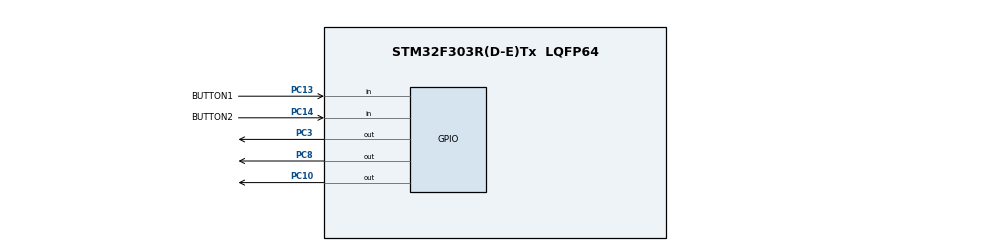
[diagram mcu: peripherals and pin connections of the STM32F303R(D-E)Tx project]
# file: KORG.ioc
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Mcu.Family=STM32F3
Mcu.Name=STM32F303R(D-E)Tx
Mcu.Package=LQFP64
NVIC.PriorityGroup=NVIC_PRIORITYGROUP_4
NVIC.TIM1_UP_TIM16_IRQn=true\:0\:0\:false\:false\:true\:true\:true
PC10.Signal=GPIO_Output
PC13.GPIO_Label=BUTTON1
PC13.Signal=GPIO_Input
PC14-OSC32_IN.GPIO_Label=BUTTON2
PC14-OSC32_IN.Signal=GPIO_Input
PC3.Signal=GPIO_Output
PC8.Signal=GPIO_Output
ProjectManager.HeapSize=0x200
ProjectManager.StackSize=0x400
ProjectManager.TargetToolchain=STM32CubeIDE
RCC.AHBFreq_Value=24000000
RCC.APB1Freq_Value=24000000
RCC.APB1TimFreq_Value=24000000
RCC.APB2CLKDivider=RCC_HCLK_DIV4
RCC.APB2Freq_Value=6000000
RCC.APB2TimFreq_Value=12000000
RCC.CortexFreq_Value=24000000
RCC.HCLKFreq_Value=24000000
RCC.HSE_VALUE=8000000
RCC.HSI_VALUE=8000000
RCC.LSE_VALUE=32768
RCC.PLLMUL=RCC_PLL_MUL3
RCC.SYSCLKFreq_VALUE=24000000
RCC.SYSCLKSourceVirtual=RCC_SYSCLKSOURCE_PLLCLK
RCC.USBFreq_Value=24000000
TIM1.Period=3999
TIM1.TIM_MasterOutputTrigger=TIM_TRGO_UPDATE
VP_TIM1_VS_ClockSourceINT.Mode=Internal
board=custom

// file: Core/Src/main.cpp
/* USER CODE BEGIN Header */
/**
  ******************************************************************************
  * @file           : main.c
  * @brief          : Main program body
  ******************************************************************************
  * @attention
  *
  * <h2><center>&copy; Copyright (c) 2022 STMicroelectronics.
  * All rights reserved.</center></h2>
  *
  * This software component is licensed by ST under BSD 3-Clause license,
  * the "License"; You may not use this file except in compliance with the
  * License. You may obtain a copy of the License at:
  *                        opensource.org/licenses/BSD-3-Clause
  *
  ******************************************************************************
  */
/* USER CODE END Header */

#include <main.hpp>

/* USER CODE BEGIN Includes */
#include <led.hpp>
/* USER CODE END Includes */

TIM_HandleTypeDef htim1;

/* USER CODE BEGIN PV */
IO::Led LED_PWR;
IO::Led LED_CLIP;
IO::Led LED_SW1;

/* USER CODE END PV */

void SystemClock_Config(void);
static void MX_GPIO_Init(void);
static void MX_TIM1_Init(void);

int main(void)
{

  /* MCU Configuration--------------------------------------------------------*/

  /* Reset of all peripherals, Initializes the Flash interface and the Systick. */
  HAL_Init();

  /* Configure the system clock */
  SystemClock_Config();

  /* USER CODE BEGIN SysInit */

  //Initialize LEDs here
  //setup TimerCallback frequency done in MX_TIM1_Init()
  LED_PWR.init(GPIOC, GPIO_PIN_3);
  LED_CLIP.init(GPIOC, GPIO_PIN_8);
  LED_SW1.init(GPIOC, GPIO_PIN_10);
  /* USER CODE END SysInit */

  /* Initialize all configured peripherals */
  MX_GPIO_Init();
  MX_TIM1_Init();
  /* USER CODE BEGIN 2 */

  //Timer started, updates generated at 6kHz
  HAL_TIM_Base_Start_IT(&htim1);
  //set LED_PWR to breathe
  LED_PWR.currentState = BREATHE;
  //set LED_SW1 on
  LED_SW1.currentState = ON;
  //set LED_CLIP to 20% brightness
  LED_CLIP.dim(20);

  /* USER CODE END 2 */

  /* Infinite loop */
  /* USER CODE BEGIN WHILE */
  while (1)
  {
	  //when button 1 is pressed, toggle LED_SW1
	  if(HAL_GPIO_ReadPin(BUTTON1_GPIO_Port, BUTTON1_Pin) == GPIO_PIN_RESET){
		  //debounce of button
		  HAL_Delay(50);
		  if(HAL_GPIO_ReadPin(BUTTON1_GPIO_Port, BUTTON1_Pin) == GPIO_PIN_RESET){
			  if(LED_SW1.currentState == OFF)
				  LED_SW1.currentState = ON;
			  else
				  LED_SW1.currentState = OFF;
		  }
		  HAL_Delay(500);
	  }

	  //when button 2 is pressed, blink and hold on LED_CLIP
	  if(HAL_GPIO_ReadPin(BUTTON2_GPIO_Port, BUTTON2_Pin) == GPIO_PIN_RESET){
		  //debounce of button
		  HAL_Delay(50);
		  if(HAL_GPIO_ReadPin(BUTTON2_GPIO_Port, BUTTON2_Pin) == GPIO_PIN_RESET){
			  LED_CLIP.blinkHoldOn();
		  }
	  }
    /* USER CODE END WHILE */

  }
}

void SystemClock_Config(void)
{
  RCC_OscInitTypeDef RCC_OscInitStruct = {0};
  RCC_ClkInitTypeDef RCC_ClkInitStruct = {0};
  RCC_PeriphCLKInitTypeDef PeriphClkInit = {0};

  /** Initializes the CPU, AHB and APB busses clocks
  */
  RCC_OscInitStruct.OscillatorType = RCC_OSCILLATORTYPE_HSI;
  RCC_OscInitStruct.HSIState = RCC_HSI_ON;
  RCC_OscInitStruct.HSICalibrationValue = RCC_HSICALIBRATION_DEFAULT;
  RCC_OscInitStruct.PLL.PLLState = RCC_PLL_ON;
  RCC_OscInitStruct.PLL.PLLSource = RCC_PLLSOURCE_HSI;
  RCC_OscInitStruct.PLL.PLLMUL = RCC_PLL_MUL3;
  RCC_OscInitStruct.PLL.PREDIV = RCC_PREDIV_DIV1;
  if (HAL_RCC_OscConfig(&RCC_OscInitStruct) != HAL_OK)
  {
    Error_Handler();
  }
  /** Initializes the CPU, AHB and APB busses clocks
  */
  RCC_ClkInitStruct.ClockType = RCC_CLOCKTYPE_HCLK|RCC_CLOCKTYPE_SYSCLK
                              |RCC_CLOCKTYPE_PCLK1|RCC_CLOCKTYPE_PCLK2;
  RCC_ClkInitStruct.SYSCLKSource = RCC_SYSCLKSOURCE_PLLCLK;
  RCC_ClkInitStruct.AHBCLKDivider = RCC_SYSCLK_DIV1;
  RCC_ClkInitStruct.APB1CLKDivider = RCC_HCLK_DIV8;
  RCC_ClkInitStruct.APB2CLKDivider = RCC_HCLK_DIV1;

  if (HAL_RCC_ClockConfig(&RCC_ClkInitStruct, FLASH_LATENCY_0) != HAL_OK)
  {
    Error_Handler();
  }
  PeriphClkInit.PeriphClockSelection = RCC_PERIPHCLK_TIM1;
  PeriphClkInit.Tim1ClockSelection = RCC_TIM1CLK_HCLK;
  if (HAL_RCCEx_PeriphCLKConfig(&PeriphClkInit) != HAL_OK)
  {
    Error_Handler();
  }
}

static void MX_TIM1_Init(void)
{

  TIM_ClockConfigTypeDef sClockSourceConfig = {0};
  TIM_MasterConfigTypeDef sMasterConfig = {0};

  htim1.Instance = TIM1;
  htim1.Init.Prescaler = 0;
  htim1.Init.CounterMode = TIM_COUNTERMODE_UP;
  htim1.Init.Period = 3999;
  htim1.Init.ClockDivision = TIM_CLOCKDIVISION_DIV1;
  htim1.Init.RepetitionCounter = 0;
  htim1.Init.AutoReloadPreload = TIM_AUTORELOAD_PRELOAD_DISABLE;
  if (HAL_TIM_Base_Init(&htim1) != HAL_OK)
  {
    Error_Handler();
  }
  sClockSourceConfig.ClockSource = TIM_CLOCKSOURCE_INTERNAL;
  if (HAL_TIM_ConfigClockSource(&htim1, &sClockSourceConfig) != HAL_OK)
  {
    Error_Handler();
  }
  sMasterConfig.MasterOutputTrigger = TIM_TRGO_UPDATE;
  sMasterConfig.MasterOutputTrigger2 = TIM_TRGO2_RESET;
  sMasterConfig.MasterSlaveMode = TIM_MASTERSLAVEMODE_DISABLE;
  if (HAL_TIMEx_MasterConfigSynchronization(&htim1, &sMasterConfig) != HAL_OK)
  {
    Error_Handler();
  }

}

static void MX_GPIO_Init(void)
{
  GPIO_InitTypeDef GPIO_InitStruct = {0};

  /* GPIO Ports Clock Enable */
  __HAL_RCC_GPIOC_CLK_ENABLE();

  /*Configure GPIO pin Output Level */
  HAL_GPIO_WritePin(GPIOC, GPIO_PIN_3|GPIO_PIN_8|GPIO_PIN_10, GPIO_PIN_RESET);

  /*Configure GPIO pins : BUTTON1_Pin BUTTON2_Pin */
  GPIO_InitStruct.Pin = BUTTON1_Pin|BUTTON2_Pin;
  GPIO_InitStruct.Mode = GPIO_MODE_INPUT;
  GPIO_InitStruct.Pull = GPIO_NOPULL;
  HAL_GPIO_Init(GPIOC, &GPIO_InitStruct);

  /*Configure GPIO pins : PC3 PC8 PC10 */
  GPIO_InitStruct.Pin = GPIO_PIN_3|GPIO_PIN_8|GPIO_PIN_10;
  GPIO_InitStruct.Mode = GPIO_MODE_OUTPUT_PP;
  GPIO_InitStruct.Pull = GPIO_NOPULL;
  GPIO_InitStruct.Speed = GPIO_SPEED_FREQ_LOW;
  HAL_GPIO_Init(GPIOC, &GPIO_InitStruct);

}

/* USER CODE BEGIN 4 */
void HAL_TIM_PeriodElapsedCallback(TIM_HandleTypeDef *htim)
{
//	HAL_GPIO_WritePin(GPIOC, GPIO_PIN_10,GPIO_PIN_SET);
//	HAL_GPIO_WritePin(GPIOC, GPIO_PIN_10,GPIO_PIN_RESET);
	LED_PWR.update();
	LED_CLIP.update();
	LED_SW1.update();
}
/* USER CODE END 4 */

void Error_Handler(void)
{
}

/************************ (C) COPYRIGHT STMicroelectronics *****END OF FILE****/
